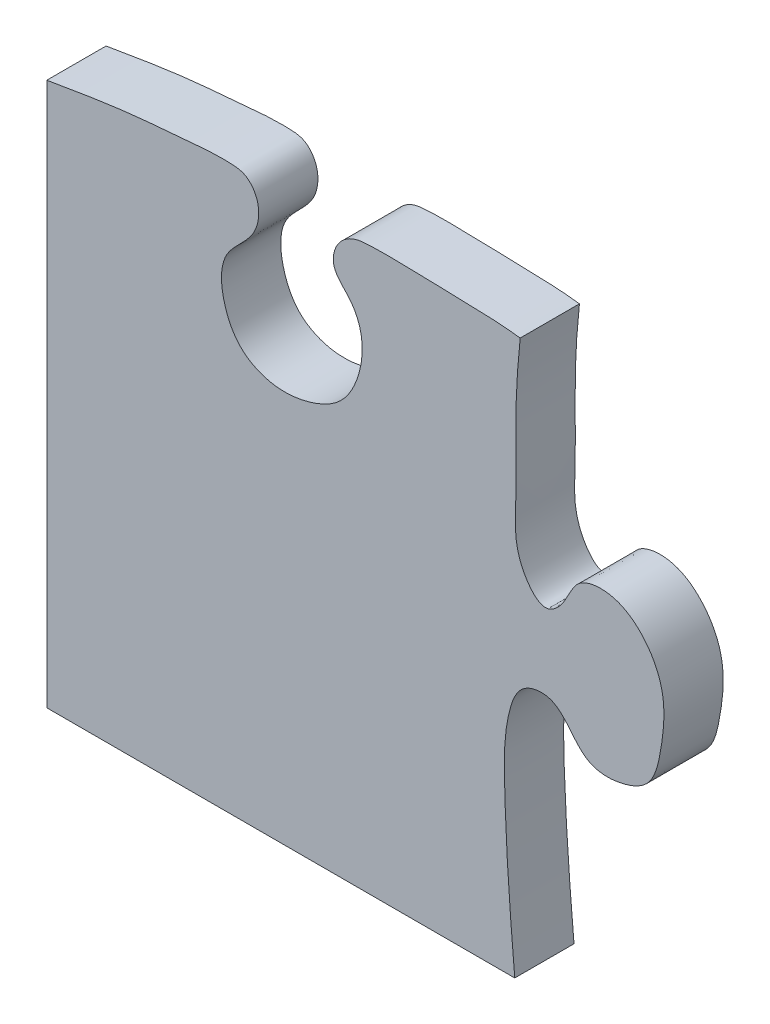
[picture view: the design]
ISO-10303-21;
HEADER;
FILE_DESCRIPTION(('STEP AP214'),'2;1');
FILE_NAME('part.step','',(''),(''),'','','');
FILE_SCHEMA(('AUTOMOTIVE_DESIGN { 1 0 10303 214 1 1 1 1 }'));
ENDSEC;
DATA;
#1=APPLICATION_CONTEXT('core data for automotive mechanical design processes');
#2=APPLICATION_PROTOCOL_DEFINITION('international standard','automotive_design',2000,#1);
#3=PRODUCT_CONTEXT('',#1,'mechanical');
#4=PRODUCT('Part','Part','',(#3));
#5=PRODUCT_RELATED_PRODUCT_CATEGORY('part','',(#4));
#6=PRODUCT_DEFINITION_FORMATION('','',#4);
#7=PRODUCT_DEFINITION_CONTEXT('part definition',#1,'design');
#8=PRODUCT_DEFINITION('design','',#6,#7);
#9=PRODUCT_DEFINITION_SHAPE('','',#8);
#10=(LENGTH_UNIT() NAMED_UNIT(*) SI_UNIT(.MILLI.,.METRE.));
#11=(NAMED_UNIT(*) PLANE_ANGLE_UNIT() SI_UNIT($,.RADIAN.));
#12=(NAMED_UNIT(*) SI_UNIT($,.STERADIAN.) SOLID_ANGLE_UNIT());
#13=UNCERTAINTY_MEASURE_WITH_UNIT(LENGTH_MEASURE(1.E-05),#10,'distance_accuracy_value','');
#14=(GEOMETRIC_REPRESENTATION_CONTEXT(3) GLOBAL_UNCERTAINTY_ASSIGNED_CONTEXT((#13)) GLOBAL_UNIT_ASSIGNED_CONTEXT((#10,
#11,#12)) REPRESENTATION_CONTEXT('',''));
#15=CARTESIAN_POINT('',(0.,0.,0.));
#16=DIRECTION('',(0.,0.,1.));
#17=DIRECTION('',(1.,0.,0.));
#18=AXIS2_PLACEMENT_3D('',#15,#16,#17);
#19=CARTESIAN_POINT('',(-352.534626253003,356.,-0.00999999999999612));
#20=CARTESIAN_POINT('',(-353.877781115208,341.802611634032,-0.00999999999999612));
#21=CARTESIAN_POINT('',(-351.460483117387,322.567956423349,-0.00999999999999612));
#22=CARTESIAN_POINT('',(-355.747404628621,299.493999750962,-0.00999999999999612));
#23=CARTESIAN_POINT('',(-347.645743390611,289.357079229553,-0.00999999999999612));
#24=CARTESIAN_POINT('',(-337.80105524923,293.322704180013,-0.00999999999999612));
#25=CARTESIAN_POINT('',(-331.763521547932,304.464683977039,-0.00999999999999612));
#26=CARTESIAN_POINT('',(-312.737993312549,300.417040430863,-0.00999999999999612));
#27=CARTESIAN_POINT('',(-304.311514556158,284.867329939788,-0.00999999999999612));
#28=CARTESIAN_POINT('',(-301.362858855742,267.518539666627,-0.00999999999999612));
#29=CARTESIAN_POINT('',(-309.525260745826,253.299800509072,-0.00999999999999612));
#30=CARTESIAN_POINT('',(-323.085028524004,249.130779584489,-0.00999999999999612));
#31=CARTESIAN_POINT('',(-333.558735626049,254.453066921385,-0.00999999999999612));
#32=CARTESIAN_POINT('',(-338.061007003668,263.306234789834,-0.00999999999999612));
#33=CARTESIAN_POINT('',(-357.610347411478,266.663664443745,-0.00999999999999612));
#34=CARTESIAN_POINT('',(-352.91397083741,227.568949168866,-0.00999999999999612));
#35=CARTESIAN_POINT('',(-349.689076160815,203.209436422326,-0.00999999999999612));
#36=CARTESIAN_POINT('',(-346.386977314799,175.800103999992,-0.00999999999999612));
#37=CARTESIAN_POINT('',(-343.691373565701,150.269708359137,-0.00999999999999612));
#38=CARTESIAN_POINT('',(-342.931567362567,128.594211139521,-0.00999999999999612));
#39=CARTESIAN_POINT('',(-343.655360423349,107.633085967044,-0.00999999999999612));
#40=CARTESIAN_POINT('',(-357.389603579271,103.824438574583,-0.00999999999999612));
#41=CARTESIAN_POINT('',(-367.576419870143,106.015828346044,-0.00999999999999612));
#42=CARTESIAN_POINT('',(-371.765750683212,114.589953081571,-0.00999999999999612));
#43=CARTESIAN_POINT('',(-382.535012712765,116.182843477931,-0.00999999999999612));
#44=CARTESIAN_POINT('',(-394.783984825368,115.916744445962,-0.00999999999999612));
#45=CARTESIAN_POINT('',(-402.322369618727,104.396558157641,-0.00999999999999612));
#46=CARTESIAN_POINT('',(-405.688784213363,89.1486295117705,-0.00999999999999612));
#47=CARTESIAN_POINT('',(-402.964002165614,71.2455616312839,-0.00999999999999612));
#48=CARTESIAN_POINT('',(-389.022909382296,60.8761001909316,-0.00999999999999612));
#49=CARTESIAN_POINT('',(-377.013010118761,63.0649709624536,-0.00999999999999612));
#50=CARTESIAN_POINT('',(-370.136212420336,70.9200889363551,-0.00999999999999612));
#51=CARTESIAN_POINT('',(-359.248489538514,74.3793713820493,-0.00999999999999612));
#52=CARTESIAN_POINT('',(-347.964757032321,70.4189230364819,-0.00999999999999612));
#53=CARTESIAN_POINT('',(-342.961480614,58.8762689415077,-0.00999999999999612));
#54=CARTESIAN_POINT('',(-344.957853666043,42.6141567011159,-0.00999999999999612));
#55=CARTESIAN_POINT('',(-348.090347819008,20.9428011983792,-0.00999999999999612));
#56=CARTESIAN_POINT('',(-348.787112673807,-1.92187291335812,-0.00999999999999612));
#57=CARTESIAN_POINT('',(-347.063507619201,-23.1354473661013,-0.00999999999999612));
#58=CARTESIAN_POINT('',(-345.803834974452,-40.1989543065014,-0.00999999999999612));
#59=CARTESIAN_POINT('',(-346.365109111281,-52.5147126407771,-0.00999999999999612));
#60=CARTESIAN_POINT('',(-346.987719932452,-61.0081322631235,-0.00999999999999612));
#61=CARTESIAN_POINT('',(-354.605588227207,-67.8105997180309,-0.00999999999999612));
#62=CARTESIAN_POINT('',(-368.483652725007,-69.9483525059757,-0.00999999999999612));
#63=CARTESIAN_POINT('',(-374.929468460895,-56.6181815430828,-0.00999999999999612));
#64=CARTESIAN_POINT('',(-389.51528778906,-54.9578642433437,-0.00999999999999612));
#65=CARTESIAN_POINT('',(-403.927113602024,-62.7741481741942,-0.00999999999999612));
#66=CARTESIAN_POINT('',(-408.906740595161,-79.6272624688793,-0.00999999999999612));
#67=CARTESIAN_POINT('',(-407.354009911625,-95.181625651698,-0.00999999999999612));
#68=CARTESIAN_POINT('',(-399.108136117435,-108.127376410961,-0.00999999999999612));
#69=CARTESIAN_POINT('',(-382.721304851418,-112.332091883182,-0.00999999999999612));
#70=CARTESIAN_POINT('',(-372.627066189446,-99.6029758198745,-0.00999999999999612));
#71=CARTESIAN_POINT('',(-359.245942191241,-98.6507630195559,-0.00999999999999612));
#72=CARTESIAN_POINT('',(-346.811479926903,-105.357996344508,-0.00999999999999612));
#73=CARTESIAN_POINT('',(-347.06309899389,-122.824759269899,-0.00999999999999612));
#74=CARTESIAN_POINT('',(-349.512128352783,-142.867981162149,-0.00999999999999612));
#75=CARTESIAN_POINT('',(-351.967561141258,-164.813498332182,-0.00999999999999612));
#76=CARTESIAN_POINT('',(-354.173348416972,-189.531702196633,-0.00999999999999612));
#77=CARTESIAN_POINT('',(-353.048503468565,-212.668893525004,-0.00999999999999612));
#78=CARTESIAN_POINT('',(-354.739062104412,-232.840407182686,-0.00999999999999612));
#79=CARTESIAN_POINT('',(-344.245211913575,-244.921596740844,-0.00999999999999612));
#80=CARTESIAN_POINT('',(-336.376475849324,-237.735778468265,-0.00999999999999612));
#81=CARTESIAN_POINT('',(-333.938993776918,-228.321764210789,-0.00999999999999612));
#82=CARTESIAN_POINT('',(-321.423877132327,-226.689197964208,-0.00999999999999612));
#83=CARTESIAN_POINT('',(-310.83224361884,-232.911014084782,-0.00999999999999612));
#84=CARTESIAN_POINT('',(-302.540379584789,-246.611975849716,-0.00999999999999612));
#85=CARTESIAN_POINT('',(-304.049270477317,-262.348985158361,-0.00999999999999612));
#86=CARTESIAN_POINT('',(-307.19247660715,-276.895908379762,-0.00999999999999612));
#87=CARTESIAN_POINT('',(-317.916754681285,-281.774853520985,-0.00999999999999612));
#88=CARTESIAN_POINT('',(-328.48323529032,-282.130896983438,-0.00999999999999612));
#89=CARTESIAN_POINT('',(-335.177873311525,-274.391757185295,-0.00999999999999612));
#90=CARTESIAN_POINT('',(-340.967044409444,-267.020526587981,-0.00999999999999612));
#91=CARTESIAN_POINT('',(-352.493784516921,-268.657509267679,-0.00999999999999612));
#92=CARTESIAN_POINT('',(-357.686319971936,-282.822093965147,-0.00999999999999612));
#93=CARTESIAN_POINT('',(-357.597756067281,-311.53856504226,-0.00999999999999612));
#94=CARTESIAN_POINT('',(-355.656952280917,-337.76537977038,-0.00999999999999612));
#95=CARTESIAN_POINT('',(-354.035135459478,-356.,-0.00999999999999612));
#96=B_SPLINE_CURVE_WITH_KNOTS('',3,(#19,#20,#21,#22,#23,#24,#25,#26,#27,#28,#29,#30,#31,#32,#33,
#34,#35,#36,#37,#38,#39,#40,#41,#42,#43,#44,#45,#46,#47,#48,#49,#50,#51,#52,#53,#54,#55,#56,#57,
#58,#59,#60,#61,#62,#63,#64,#65,#66,#67,#68,#69,#70,#71,#72,#73,#74,#75,#76,#77,#78,#79,#80,#81,
#82,#83,#84,#85,#86,#87,#88,#89,#90,#91,#92,#93,#94,#95),.UNSPECIFIED.,.F.,.F.,(4,1,1,1,1,1,1,1,
1,1,1,1,1,1,1,1,1,1,1,1,1,1,1,1,1,1,1,1,1,1,1,1,1,1,1,1,1,1,1,1,1,1,1,1,1,1,1,1,1,1,1,1,1,1,1,1,
1,1,1,1,1,1,1,1,1,1,1,1,1,1,1,1,1,1,4),(0.,0.0362663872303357,0.0516957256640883,
0.0575126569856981,0.0656061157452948,0.0738542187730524,0.0886191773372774,0.103761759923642,
0.118344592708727,0.132658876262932,0.141706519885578,0.152628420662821,0.159936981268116,
0.166346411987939,0.196099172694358,0.222591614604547,0.242329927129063,0.265519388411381,
0.28892287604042,0.3014399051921,0.313339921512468,0.3200215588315,0.327007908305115,
0.335496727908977,0.346341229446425,0.356695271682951,0.367736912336,0.387395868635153,
0.399447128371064,0.408443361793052,0.416078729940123,0.425886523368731,0.4364139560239,
0.44355209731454,0.456701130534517,0.478081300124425,0.500737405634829,0.515722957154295,
0.53328305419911,0.545176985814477,0.547408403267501,0.555597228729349,0.568417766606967,
0.576959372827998,0.589646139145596,0.601337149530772,0.617107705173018,0.631663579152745,
0.64088779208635,0.655943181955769,0.666193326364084,0.679689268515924,0.687162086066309,
0.700019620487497,0.719317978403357,0.742088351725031,0.756487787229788,0.783860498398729,
0.801622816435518,0.8097052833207,0.815461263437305,0.824516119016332,0.833497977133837,
0.842909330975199,0.85562007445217,0.872330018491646,0.883598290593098,0.890881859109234,
0.901363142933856,0.908021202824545,0.916645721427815,0.924017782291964,0.933106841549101,
0.95201687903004,1.),.UNSPECIFIED.);
#97=DIRECTION('',(0.,0.,1.));
#98=VECTOR('',#97,1.);
#99=SURFACE_OF_LINEAR_EXTRUSION('',#96,#98);
#100=CARTESIAN_POINT('',(-352.534626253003,356.,20.));
#101=CARTESIAN_POINT('',(-353.877781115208,341.802611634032,20.));
#102=CARTESIAN_POINT('',(-351.460483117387,322.567956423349,20.));
#103=CARTESIAN_POINT('',(-355.747404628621,299.493999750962,20.));
#104=CARTESIAN_POINT('',(-347.645743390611,289.357079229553,20.));
#105=CARTESIAN_POINT('',(-337.80105524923,293.322704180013,20.));
#106=CARTESIAN_POINT('',(-331.763521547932,304.464683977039,20.));
#107=CARTESIAN_POINT('',(-312.737993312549,300.417040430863,20.));
#108=CARTESIAN_POINT('',(-304.311514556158,284.867329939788,20.));
#109=CARTESIAN_POINT('',(-301.362858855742,267.518539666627,20.));
#110=CARTESIAN_POINT('',(-309.525260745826,253.299800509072,20.));
#111=CARTESIAN_POINT('',(-323.085028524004,249.130779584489,20.));
#112=CARTESIAN_POINT('',(-333.558735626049,254.453066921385,20.));
#113=CARTESIAN_POINT('',(-338.061007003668,263.306234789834,20.));
#114=CARTESIAN_POINT('',(-357.610347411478,266.663664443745,20.));
#115=CARTESIAN_POINT('',(-352.91397083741,227.568949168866,20.));
#116=CARTESIAN_POINT('',(-349.689076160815,203.209436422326,20.));
#117=CARTESIAN_POINT('',(-346.386977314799,175.800103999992,20.));
#118=CARTESIAN_POINT('',(-343.691373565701,150.269708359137,20.));
#119=CARTESIAN_POINT('',(-342.931567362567,128.594211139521,20.));
#120=CARTESIAN_POINT('',(-343.655360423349,107.633085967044,20.));
#121=CARTESIAN_POINT('',(-357.389603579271,103.824438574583,20.));
#122=CARTESIAN_POINT('',(-367.576419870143,106.015828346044,20.));
#123=CARTESIAN_POINT('',(-371.765750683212,114.589953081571,20.));
#124=CARTESIAN_POINT('',(-382.535012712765,116.182843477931,20.));
#125=CARTESIAN_POINT('',(-394.783984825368,115.916744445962,20.));
#126=CARTESIAN_POINT('',(-402.322369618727,104.396558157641,20.));
#127=CARTESIAN_POINT('',(-405.688784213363,89.1486295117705,20.));
#128=CARTESIAN_POINT('',(-402.964002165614,71.2455616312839,20.));
#129=CARTESIAN_POINT('',(-389.022909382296,60.8761001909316,20.));
#130=CARTESIAN_POINT('',(-377.013010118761,63.0649709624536,20.));
#131=CARTESIAN_POINT('',(-370.136212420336,70.9200889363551,20.));
#132=CARTESIAN_POINT('',(-359.248489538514,74.3793713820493,20.));
#133=CARTESIAN_POINT('',(-347.964757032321,70.4189230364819,20.));
#134=CARTESIAN_POINT('',(-342.961480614,58.8762689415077,20.));
#135=CARTESIAN_POINT('',(-344.957853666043,42.6141567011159,20.));
#136=CARTESIAN_POINT('',(-348.090347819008,20.9428011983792,20.));
#137=CARTESIAN_POINT('',(-348.787112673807,-1.92187291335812,20.));
#138=CARTESIAN_POINT('',(-347.063507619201,-23.1354473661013,20.));
#139=CARTESIAN_POINT('',(-345.803834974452,-40.1989543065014,20.));
#140=CARTESIAN_POINT('',(-346.365109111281,-52.5147126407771,20.));
#141=CARTESIAN_POINT('',(-346.987719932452,-61.0081322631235,20.));
#142=CARTESIAN_POINT('',(-354.605588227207,-67.8105997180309,20.));
#143=CARTESIAN_POINT('',(-368.483652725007,-69.9483525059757,20.));
#144=CARTESIAN_POINT('',(-374.929468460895,-56.6181815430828,20.));
#145=CARTESIAN_POINT('',(-389.51528778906,-54.9578642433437,20.));
#146=CARTESIAN_POINT('',(-403.927113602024,-62.7741481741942,20.));
#147=CARTESIAN_POINT('',(-408.906740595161,-79.6272624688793,20.));
#148=CARTESIAN_POINT('',(-407.354009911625,-95.181625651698,20.));
#149=CARTESIAN_POINT('',(-399.108136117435,-108.127376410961,20.));
#150=CARTESIAN_POINT('',(-382.721304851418,-112.332091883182,20.));
#151=CARTESIAN_POINT('',(-372.627066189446,-99.6029758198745,20.));
#152=CARTESIAN_POINT('',(-359.245942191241,-98.6507630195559,20.));
#153=CARTESIAN_POINT('',(-346.811479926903,-105.357996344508,20.));
#154=CARTESIAN_POINT('',(-347.06309899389,-122.824759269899,20.));
#155=CARTESIAN_POINT('',(-349.512128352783,-142.867981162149,20.));
#156=CARTESIAN_POINT('',(-351.967561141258,-164.813498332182,20.));
#157=CARTESIAN_POINT('',(-354.173348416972,-189.531702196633,20.));
#158=CARTESIAN_POINT('',(-353.048503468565,-212.668893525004,20.));
#159=CARTESIAN_POINT('',(-354.739062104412,-232.840407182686,20.));
#160=CARTESIAN_POINT('',(-344.245211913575,-244.921596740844,20.));
#161=CARTESIAN_POINT('',(-336.376475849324,-237.735778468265,20.));
#162=CARTESIAN_POINT('',(-333.938993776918,-228.321764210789,20.));
#163=CARTESIAN_POINT('',(-321.423877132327,-226.689197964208,20.));
#164=CARTESIAN_POINT('',(-310.83224361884,-232.911014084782,20.));
#165=CARTESIAN_POINT('',(-302.540379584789,-246.611975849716,20.));
#166=CARTESIAN_POINT('',(-304.049270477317,-262.348985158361,20.));
#167=CARTESIAN_POINT('',(-307.19247660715,-276.895908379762,20.));
#168=CARTESIAN_POINT('',(-317.916754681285,-281.774853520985,20.));
#169=CARTESIAN_POINT('',(-328.48323529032,-282.130896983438,20.));
#170=CARTESIAN_POINT('',(-335.177873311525,-274.391757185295,20.));
#171=CARTESIAN_POINT('',(-340.967044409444,-267.020526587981,20.));
#172=CARTESIAN_POINT('',(-352.493784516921,-268.657509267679,20.));
#173=CARTESIAN_POINT('',(-357.686319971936,-282.822093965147,20.));
#174=CARTESIAN_POINT('',(-357.597756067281,-311.53856504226,20.));
#175=CARTESIAN_POINT('',(-355.656952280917,-337.76537977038,20.));
#176=CARTESIAN_POINT('',(-354.035135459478,-356.,20.));
#177=B_SPLINE_CURVE_WITH_KNOTS('',3,(#100,#101,#102,#103,#104,#105,#106,#107,#108,#109,#110,
#111,#112,#113,#114,#115,#116,#117,#118,#119,#120,#121,#122,#123,#124,#125,#126,#127,#128,#129,
#130,#131,#132,#133,#134,#135,#136,#137,#138,#139,#140,#141,#142,#143,#144,#145,#146,#147,#148,
#149,#150,#151,#152,#153,#154,#155,#156,#157,#158,#159,#160,#161,#162,#163,#164,#165,#166,#167,
#168,#169,#170,#171,#172,#173,#174,#175,#176),.UNSPECIFIED.,.F.,.F.,(4,1,1,1,1,1,1,1,1,1,1,1,1,
1,1,1,1,1,1,1,1,1,1,1,1,1,1,1,1,1,1,1,1,1,1,1,1,1,1,1,1,1,1,1,1,1,1,1,1,1,1,1,1,1,1,1,1,1,1,1,1,
1,1,1,1,1,1,1,1,1,1,1,1,1,4),(0.,0.0362663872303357,0.0516957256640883,0.0575126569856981,
0.0656061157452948,0.0738542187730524,0.0886191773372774,0.103761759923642,0.118344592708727,
0.132658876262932,0.141706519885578,0.152628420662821,0.159936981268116,0.166346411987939,
0.196099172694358,0.222591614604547,0.242329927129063,0.265519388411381,0.28892287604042,
0.3014399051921,0.313339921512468,0.3200215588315,0.327007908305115,0.335496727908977,
0.346341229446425,0.356695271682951,0.367736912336,0.387395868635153,0.399447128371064,
0.408443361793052,0.416078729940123,0.425886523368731,0.4364139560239,0.44355209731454,
0.456701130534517,0.478081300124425,0.500737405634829,0.515722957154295,0.53328305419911,
0.545176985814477,0.547408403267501,0.555597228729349,0.568417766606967,0.576959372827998,
0.589646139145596,0.601337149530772,0.617107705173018,0.631663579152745,0.64088779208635,
0.655943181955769,0.666193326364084,0.679689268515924,0.687162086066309,0.700019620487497,
0.719317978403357,0.742088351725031,0.756487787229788,0.783860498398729,0.801622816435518,
0.8097052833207,0.815461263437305,0.824516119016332,0.833497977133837,0.842909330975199,
0.85562007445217,0.872330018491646,0.883598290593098,0.890881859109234,0.901363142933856,
0.908021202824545,0.916645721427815,0.924017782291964,0.933106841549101,0.95201687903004,1.),.UNSPECIFIED.);
#178=CARTESIAN_POINT('',(-352.201722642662,-167.987791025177,20.));
#179=VERTEX_POINT('',#178);
#180=CARTESIAN_POINT('',(-354.035135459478,-356.,20.));
#181=VERTEX_POINT('',#180);
#182=EDGE_CURVE('E80',#179,#181,#177,.T.);
#183=ORIENTED_EDGE('',*,*,#182,.T.);
#184=DIRECTION('',(0.,0.,1.));
#185=VECTOR('',#184,1.);
#186=CARTESIAN_POINT('',(-354.035135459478,-356.,-0.00999999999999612));
#187=LINE('',#186,#185);
#188=CARTESIAN_POINT('',(-354.035135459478,-356.,0.));
#189=VERTEX_POINT('',#188);
#190=EDGE_CURVE('E83',#189,#181,#187,.T.);
#191=ORIENTED_EDGE('',*,*,#190,.F.);
#192=CARTESIAN_POINT('',(-352.534626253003,356.,0.));
#193=CARTESIAN_POINT('',(-353.877781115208,341.802611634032,0.));
#194=CARTESIAN_POINT('',(-351.460483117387,322.567956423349,0.));
#195=CARTESIAN_POINT('',(-355.747404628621,299.493999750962,0.));
#196=CARTESIAN_POINT('',(-347.645743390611,289.357079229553,0.));
#197=CARTESIAN_POINT('',(-337.80105524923,293.322704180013,0.));
#198=CARTESIAN_POINT('',(-331.763521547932,304.464683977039,0.));
#199=CARTESIAN_POINT('',(-312.737993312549,300.417040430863,0.));
#200=CARTESIAN_POINT('',(-304.311514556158,284.867329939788,0.));
#201=CARTESIAN_POINT('',(-301.362858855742,267.518539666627,0.));
#202=CARTESIAN_POINT('',(-309.525260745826,253.299800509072,0.));
#203=CARTESIAN_POINT('',(-323.085028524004,249.130779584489,0.));
#204=CARTESIAN_POINT('',(-333.558735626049,254.453066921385,0.));
#205=CARTESIAN_POINT('',(-338.061007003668,263.306234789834,0.));
#206=CARTESIAN_POINT('',(-357.610347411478,266.663664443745,0.));
#207=CARTESIAN_POINT('',(-352.91397083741,227.568949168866,0.));
#208=CARTESIAN_POINT('',(-349.689076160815,203.209436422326,0.));
#209=CARTESIAN_POINT('',(-346.386977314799,175.800103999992,0.));
#210=CARTESIAN_POINT('',(-343.691373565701,150.269708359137,0.));
#211=CARTESIAN_POINT('',(-342.931567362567,128.594211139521,0.));
#212=CARTESIAN_POINT('',(-343.655360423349,107.633085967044,0.));
#213=CARTESIAN_POINT('',(-357.389603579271,103.824438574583,0.));
#214=CARTESIAN_POINT('',(-367.576419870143,106.015828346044,0.));
#215=CARTESIAN_POINT('',(-371.765750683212,114.589953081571,0.));
#216=CARTESIAN_POINT('',(-382.535012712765,116.182843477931,0.));
#217=CARTESIAN_POINT('',(-394.783984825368,115.916744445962,0.));
#218=CARTESIAN_POINT('',(-402.322369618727,104.396558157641,0.));
#219=CARTESIAN_POINT('',(-405.688784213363,89.1486295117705,0.));
#220=CARTESIAN_POINT('',(-402.964002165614,71.2455616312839,0.));
#221=CARTESIAN_POINT('',(-389.022909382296,60.8761001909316,0.));
#222=CARTESIAN_POINT('',(-377.013010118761,63.0649709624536,0.));
#223=CARTESIAN_POINT('',(-370.136212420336,70.9200889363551,0.));
#224=CARTESIAN_POINT('',(-359.248489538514,74.3793713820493,0.));
#225=CARTESIAN_POINT('',(-347.964757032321,70.4189230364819,0.));
#226=CARTESIAN_POINT('',(-342.961480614,58.8762689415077,0.));
#227=CARTESIAN_POINT('',(-344.957853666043,42.6141567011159,0.));
#228=CARTESIAN_POINT('',(-348.090347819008,20.9428011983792,0.));
#229=CARTESIAN_POINT('',(-348.787112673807,-1.92187291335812,0.));
#230=CARTESIAN_POINT('',(-347.063507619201,-23.1354473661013,0.));
#231=CARTESIAN_POINT('',(-345.803834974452,-40.1989543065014,0.));
#232=CARTESIAN_POINT('',(-346.365109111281,-52.5147126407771,0.));
#233=CARTESIAN_POINT('',(-346.987719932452,-61.0081322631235,0.));
#234=CARTESIAN_POINT('',(-354.605588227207,-67.8105997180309,0.));
#235=CARTESIAN_POINT('',(-368.483652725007,-69.9483525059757,0.));
#236=CARTESIAN_POINT('',(-374.929468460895,-56.6181815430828,0.));
#237=CARTESIAN_POINT('',(-389.51528778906,-54.9578642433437,0.));
#238=CARTESIAN_POINT('',(-403.927113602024,-62.7741481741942,0.));
#239=CARTESIAN_POINT('',(-408.906740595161,-79.6272624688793,0.));
#240=CARTESIAN_POINT('',(-407.354009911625,-95.181625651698,0.));
#241=CARTESIAN_POINT('',(-399.108136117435,-108.127376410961,0.));
#242=CARTESIAN_POINT('',(-382.721304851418,-112.332091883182,0.));
#243=CARTESIAN_POINT('',(-372.627066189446,-99.6029758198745,0.));
#244=CARTESIAN_POINT('',(-359.245942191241,-98.6507630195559,0.));
#245=CARTESIAN_POINT('',(-346.811479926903,-105.357996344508,0.));
#246=CARTESIAN_POINT('',(-347.06309899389,-122.824759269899,0.));
#247=CARTESIAN_POINT('',(-349.512128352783,-142.867981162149,0.));
#248=CARTESIAN_POINT('',(-351.967561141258,-164.813498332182,0.));
#249=CARTESIAN_POINT('',(-354.173348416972,-189.531702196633,0.));
#250=CARTESIAN_POINT('',(-353.048503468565,-212.668893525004,0.));
#251=CARTESIAN_POINT('',(-354.739062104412,-232.840407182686,0.));
#252=CARTESIAN_POINT('',(-344.245211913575,-244.921596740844,0.));
#253=CARTESIAN_POINT('',(-336.376475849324,-237.735778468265,0.));
#254=CARTESIAN_POINT('',(-333.938993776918,-228.321764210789,0.));
#255=CARTESIAN_POINT('',(-321.423877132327,-226.689197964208,0.));
#256=CARTESIAN_POINT('',(-310.83224361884,-232.911014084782,0.));
#257=CARTESIAN_POINT('',(-302.540379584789,-246.611975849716,0.));
#258=CARTESIAN_POINT('',(-304.049270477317,-262.348985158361,0.));
#259=CARTESIAN_POINT('',(-307.19247660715,-276.895908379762,0.));
#260=CARTESIAN_POINT('',(-317.916754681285,-281.774853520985,0.));
#261=CARTESIAN_POINT('',(-328.48323529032,-282.130896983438,0.));
#262=CARTESIAN_POINT('',(-335.177873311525,-274.391757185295,0.));
#263=CARTESIAN_POINT('',(-340.967044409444,-267.020526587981,0.));
#264=CARTESIAN_POINT('',(-352.493784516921,-268.657509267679,0.));
#265=CARTESIAN_POINT('',(-357.686319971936,-282.822093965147,0.));
#266=CARTESIAN_POINT('',(-357.597756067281,-311.53856504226,0.));
#267=CARTESIAN_POINT('',(-355.656952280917,-337.76537977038,0.));
#268=CARTESIAN_POINT('',(-354.035135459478,-356.,0.));
#269=B_SPLINE_CURVE_WITH_KNOTS('',3,(#192,#193,#194,#195,#196,#197,#198,#199,#200,#201,#202,
#203,#204,#205,#206,#207,#208,#209,#210,#211,#212,#213,#214,#215,#216,#217,#218,#219,#220,#221,
#222,#223,#224,#225,#226,#227,#228,#229,#230,#231,#232,#233,#234,#235,#236,#237,#238,#239,#240,
#241,#242,#243,#244,#245,#246,#247,#248,#249,#250,#251,#252,#253,#254,#255,#256,#257,#258,#259,
#260,#261,#262,#263,#264,#265,#266,#267,#268),.UNSPECIFIED.,.F.,.F.,(4,1,1,1,1,1,1,1,1,1,1,1,1,
1,1,1,1,1,1,1,1,1,1,1,1,1,1,1,1,1,1,1,1,1,1,1,1,1,1,1,1,1,1,1,1,1,1,1,1,1,1,1,1,1,1,1,1,1,1,1,1,
1,1,1,1,1,1,1,1,1,1,1,1,1,4),(0.,0.0362663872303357,0.0516957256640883,0.0575126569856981,
0.0656061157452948,0.0738542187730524,0.0886191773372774,0.103761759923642,0.118344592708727,
0.132658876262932,0.141706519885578,0.152628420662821,0.159936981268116,0.166346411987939,
0.196099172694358,0.222591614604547,0.242329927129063,0.265519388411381,0.28892287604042,
0.3014399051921,0.313339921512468,0.3200215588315,0.327007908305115,0.335496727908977,
0.346341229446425,0.356695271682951,0.367736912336,0.387395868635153,0.399447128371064,
0.408443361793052,0.416078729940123,0.425886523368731,0.4364139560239,0.44355209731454,
0.456701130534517,0.478081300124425,0.500737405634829,0.515722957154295,0.53328305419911,
0.545176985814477,0.547408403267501,0.555597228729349,0.568417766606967,0.576959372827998,
0.589646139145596,0.601337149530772,0.617107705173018,0.631663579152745,0.64088779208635,
0.655943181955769,0.666193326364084,0.679689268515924,0.687162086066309,0.700019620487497,
0.719317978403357,0.742088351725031,0.756487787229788,0.783860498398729,0.801622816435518,
0.8097052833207,0.815461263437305,0.824516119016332,0.833497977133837,0.842909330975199,
0.85562007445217,0.872330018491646,0.883598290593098,0.890881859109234,0.901363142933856,
0.908021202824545,0.916645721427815,0.924017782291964,0.933106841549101,0.95201687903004,1.),.UNSPECIFIED.);
#270=CARTESIAN_POINT('',(-352.201722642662,-167.987791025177,0.));
#271=VERTEX_POINT('',#270);
#272=EDGE_CURVE('E82',#271,#189,#269,.T.);
#273=ORIENTED_EDGE('',*,*,#272,.F.);
#274=DIRECTION('',(0.,0.,1.));
#275=VECTOR('',#274,1.);
#276=CARTESIAN_POINT('',(-352.201722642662,-167.987791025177,-0.00999999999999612));
#277=LINE('',#276,#275);
#278=EDGE_CURVE('E78',#179,#271,#277,.F.);
#279=ORIENTED_EDGE('',*,*,#278,.F.);
#280=EDGE_LOOP('',(#183,#191,#273,#279));
#281=FACE_BOUND('',#280,.T.);
#282=ADVANCED_FACE('F34',(#281),#99,.F.);
#283=CARTESIAN_POINT('',(-512.,-172.519287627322,-0.00999999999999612));
#284=CARTESIAN_POINT('',(-502.879283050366,-170.962470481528,-0.00999999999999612));
#285=CARTESIAN_POINT('',(-487.788222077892,-168.37828827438,-0.00999999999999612));
#286=CARTESIAN_POINT('',(-467.037528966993,-166.739801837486,-0.00999999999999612));
#287=CARTESIAN_POINT('',(-454.159365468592,-165.446436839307,-0.00999999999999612));
#288=CARTESIAN_POINT('',(-444.971534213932,-166.107812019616,-0.00999999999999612));
#289=CARTESIAN_POINT('',(-439.850321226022,-171.772015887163,-0.00999999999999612));
#290=CARTESIAN_POINT('',(-440.374957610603,-181.037323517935,-0.00999999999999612));
#291=CARTESIAN_POINT('',(-446.328241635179,-187.391856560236,-0.00999999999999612));
#292=CARTESIAN_POINT('',(-453.905227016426,-194.752671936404,-0.00999999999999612));
#293=CARTESIAN_POINT('',(-453.078389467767,-207.700641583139,-0.00999999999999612));
#294=CARTESIAN_POINT('',(-447.147625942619,-218.930001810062,-0.00999999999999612));
#295=CARTESIAN_POINT('',(-435.337181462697,-224.50074852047,-0.00999999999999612));
#296=CARTESIAN_POINT('',(-423.146614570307,-223.01936726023,-0.00999999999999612));
#297=CARTESIAN_POINT('',(-411.980938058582,-217.277205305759,-0.00999999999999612));
#298=CARTESIAN_POINT('',(-406.065466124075,-206.648631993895,-0.00999999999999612));
#299=CARTESIAN_POINT('',(-404.677696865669,-194.893000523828,-0.00999999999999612));
#300=CARTESIAN_POINT('',(-408.988751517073,-185.080089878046,-0.00999999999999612));
#301=CARTESIAN_POINT('',(-416.250714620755,-179.677092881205,-0.00999999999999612));
#302=CARTESIAN_POINT('',(-414.534960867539,-170.559036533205,-0.00999999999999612));
#303=CARTESIAN_POINT('',(-409.029101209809,-166.771377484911,-0.00999999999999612));
#304=CARTESIAN_POINT('',(-399.765557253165,-166.088529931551,-0.00999999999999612));
#305=CARTESIAN_POINT('',(-387.895154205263,-166.365956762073,-0.00999999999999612));
#306=CARTESIAN_POINT('',(-370.467023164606,-166.815486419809,-0.00999999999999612));
#307=CARTESIAN_POINT('',(-353.468929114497,-167.36046909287,-0.00999999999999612));
#308=CARTESIAN_POINT('',(-335.945481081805,-171.004639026,-0.00999999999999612));
#309=CARTESIAN_POINT('',(-314.642568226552,-174.308910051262,-0.00999999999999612));
#310=CARTESIAN_POINT('',(-295.191530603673,-175.373190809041,-0.00999999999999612));
#311=CARTESIAN_POINT('',(-279.655129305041,-174.532366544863,-0.00999999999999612));
#312=CARTESIAN_POINT('',(-272.871357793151,-169.661223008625,-0.00999999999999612));
#313=CARTESIAN_POINT('',(-269.507556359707,-161.549368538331,-0.00999999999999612));
#314=CARTESIAN_POINT('',(-275.843021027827,-154.65628056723,-0.00999999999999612));
#315=CARTESIAN_POINT('',(-280.95754914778,-144.902856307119,-0.00999999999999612));
#316=CARTESIAN_POINT('',(-276.534312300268,-130.977346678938,-0.00999999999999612));
#317=CARTESIAN_POINT('',(-261.937250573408,-125.579540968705,-0.00999999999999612));
#318=CARTESIAN_POINT('',(-247.663642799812,-124.917748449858,-0.00999999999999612));
#319=CARTESIAN_POINT('',(-234.462562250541,-132.547465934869,-0.00999999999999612));
#320=CARTESIAN_POINT('',(-231.429981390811,-144.191054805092,-0.00999999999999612));
#321=CARTESIAN_POINT('',(-232.066307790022,-154.613730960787,-0.00999999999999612));
#322=CARTESIAN_POINT('',(-238.05545254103,-160.208195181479,-0.00999999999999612));
#323=CARTESIAN_POINT('',(-239.725495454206,-167.504540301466,-0.00999999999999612));
#324=CARTESIAN_POINT('',(-236.616853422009,-176.333406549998,-0.00999999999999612));
#325=CARTESIAN_POINT('',(-223.934770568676,-178.282283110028,-0.00999999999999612));
#326=CARTESIAN_POINT('',(-211.556635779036,-176.87255281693,-0.00999999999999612));
#327=CARTESIAN_POINT('',(-197.283196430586,-172.884179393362,-0.00999999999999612));
#328=CARTESIAN_POINT('',(-182.605892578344,-171.15728588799,-0.00999999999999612));
#329=CARTESIAN_POINT('',(-164.840984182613,-173.659101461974,-0.00999999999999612));
#330=CARTESIAN_POINT('',(-147.945056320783,-175.383809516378,-0.00999999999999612));
#331=CARTESIAN_POINT('',(-131.023155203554,-175.064925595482,-0.00999999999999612));
#332=CARTESIAN_POINT('',(-118.854077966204,-171.888086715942,-0.00999999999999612));
#333=CARTESIAN_POINT('',(-110.251650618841,-164.015375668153,-0.00999999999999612));
#334=CARTESIAN_POINT('',(-112.366058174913,-152.74022327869,-0.00999999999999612));
#335=CARTESIAN_POINT('',(-124.029184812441,-149.21363367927,-0.00999999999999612));
#336=CARTESIAN_POINT('',(-130.728576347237,-135.686086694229,-0.00999999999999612));
#337=CARTESIAN_POINT('',(-127.173489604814,-119.738819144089,-0.00999999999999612));
#338=CARTESIAN_POINT('',(-112.643680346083,-109.612236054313,-0.00999999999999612));
#339=CARTESIAN_POINT('',(-97.8925044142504,-110.264465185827,-0.00999999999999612));
#340=CARTESIAN_POINT('',(-85.3244606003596,-114.886626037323,-0.00999999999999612));
#341=CARTESIAN_POINT('',(-77.7012738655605,-123.996273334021,-0.00999999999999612));
#342=CARTESIAN_POINT('',(-75.1871896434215,-136.082021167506,-0.00999999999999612));
#343=CARTESIAN_POINT('',(-83.4449300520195,-145.685757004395,-0.00999999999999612));
#344=CARTESIAN_POINT('',(-93.6696383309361,-152.57821138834,-0.00999999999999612));
#345=CARTESIAN_POINT('',(-93.6908124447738,-166.777041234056,-0.00999999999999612));
#346=CARTESIAN_POINT('',(-84.1667136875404,-170.982620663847,-0.00999999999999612));
#347=CARTESIAN_POINT('',(-77.6752461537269,-173.278649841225,-0.00999999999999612));
#348=CARTESIAN_POINT('',(-68.1506335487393,-173.35598232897,-0.00999999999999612));
#349=CARTESIAN_POINT('',(-50.9086392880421,-172.467654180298,-0.00999999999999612));
#350=CARTESIAN_POINT('',(-29.3703336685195,-168.255680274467,-0.00999999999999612));
#351=CARTESIAN_POINT('',(-5.85808978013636,-161.016855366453,-0.00999999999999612));
#352=CARTESIAN_POINT('',(10.8279950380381,-157.928962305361,-0.00999999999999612));
#353=CARTESIAN_POINT('',(25.2118575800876,-156.177147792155,-0.00999999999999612));
#354=CARTESIAN_POINT('',(33.2719504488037,-161.887778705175,-0.00999999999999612));
#355=CARTESIAN_POINT('',(35.8385918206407,-171.199049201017,-0.00999999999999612));
#356=CARTESIAN_POINT('',(29.9803253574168,-178.254603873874,-0.00999999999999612));
#357=CARTESIAN_POINT('',(25.4737691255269,-186.687205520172,-0.00999999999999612));
#358=CARTESIAN_POINT('',(28.9610561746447,-203.576557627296,-0.00999999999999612));
#359=CARTESIAN_POINT('',(48.123587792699,-210.569059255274,-0.00999999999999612));
#360=CARTESIAN_POINT('',(64.640055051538,-207.443077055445,-0.00999999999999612));
#361=CARTESIAN_POINT('',(74.3525428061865,-199.315206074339,-0.00999999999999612));
#362=CARTESIAN_POINT('',(75.7823175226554,-188.025012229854,-0.00999999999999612));
#363=CARTESIAN_POINT('',(70.2823025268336,-180.424725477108,-0.00999999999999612));
#364=CARTESIAN_POINT('',(64.0173174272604,-173.04354513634,-0.00999999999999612));
#365=CARTESIAN_POINT('',(71.5185276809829,-158.021609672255,-0.00999999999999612));
#366=CARTESIAN_POINT('',(93.5727320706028,-159.248655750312,-0.00999999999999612));
#367=CARTESIAN_POINT('',(113.740225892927,-158.313305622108,-0.00999999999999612));
#368=CARTESIAN_POINT('',(131.949907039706,-158.592164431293,-0.00999999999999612));
#369=CARTESIAN_POINT('',(148.33531025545,-158.585790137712,-0.00999999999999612));
#370=CARTESIAN_POINT('',(161.926831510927,-159.545351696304,-0.00999999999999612));
#371=CARTESIAN_POINT('',(175.071227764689,-161.773214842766,-0.00999999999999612));
#372=CARTESIAN_POINT('',(191.617950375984,-167.262045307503,-0.00999999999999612));
#373=CARTESIAN_POINT('',(211.099842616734,-169.750201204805,-0.00999999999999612));
#374=CARTESIAN_POINT('',(231.162897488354,-172.887375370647,-0.00999999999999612));
#375=CARTESIAN_POINT('',(248.004345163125,-166.961938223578,-0.00999999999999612));
#376=CARTESIAN_POINT('',(246.8159561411,-153.026737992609,-0.00999999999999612));
#377=CARTESIAN_POINT('',(239.480844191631,-147.244126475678,-0.00999999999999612));
#378=CARTESIAN_POINT('',(236.934105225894,-136.316213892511,-0.00999999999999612));
#379=CARTESIAN_POINT('',(242.714843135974,-119.925321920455,-0.00999999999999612));
#380=CARTESIAN_POINT('',(261.920814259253,-116.243910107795,-0.00999999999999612));
#381=CARTESIAN_POINT('',(276.115384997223,-120.8163533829,-0.00999999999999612));
#382=CARTESIAN_POINT('',(283.920063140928,-128.519918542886,-0.00999999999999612));
#383=CARTESIAN_POINT('',(286.731045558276,-138.27620491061,-0.00999999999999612));
#384=CARTESIAN_POINT('',(285.530131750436,-148.336399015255,-0.00999999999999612));
#385=CARTESIAN_POINT('',(279.231187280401,-154.989394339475,-0.00999999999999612));
#386=CARTESIAN_POINT('',(277.47424541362,-164.19805137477,-0.00999999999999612));
#387=CARTESIAN_POINT('',(282.318065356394,-172.951788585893,-0.00999999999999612));
#388=CARTESIAN_POINT('',(296.661024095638,-174.046241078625,-0.00999999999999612));
#389=CARTESIAN_POINT('',(312.407790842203,-171.220247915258,-0.00999999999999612));
#390=CARTESIAN_POINT('',(331.258502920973,-165.499354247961,-0.00999999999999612));
#391=CARTESIAN_POINT('',(349.515462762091,-164.109048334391,-0.00999999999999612));
#392=CARTESIAN_POINT('',(369.065560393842,-162.668121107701,-0.00999999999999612));
#393=CARTESIAN_POINT('',(383.300131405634,-163.956688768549,-0.00999999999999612));
#394=CARTESIAN_POINT('',(393.167029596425,-163.158367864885,-0.00999999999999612));
#395=CARTESIAN_POINT('',(398.987630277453,-166.389896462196,-0.00999999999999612));
#396=CARTESIAN_POINT('',(404.84494808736,-173.902135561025,-0.00999999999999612));
#397=CARTESIAN_POINT('',(403.877710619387,-184.83720633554,-0.00999999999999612));
#398=CARTESIAN_POINT('',(397.972595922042,-188.779997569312,-0.00999999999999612));
#399=CARTESIAN_POINT('',(391.418741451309,-195.180814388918,-0.00999999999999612));
#400=CARTESIAN_POINT('',(389.486866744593,-207.78576343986,-0.00999999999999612));
#401=CARTESIAN_POINT('',(398.568510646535,-219.719050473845,-0.00999999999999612));
#402=CARTESIAN_POINT('',(413.367098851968,-224.627522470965,-0.00999999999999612));
#403=CARTESIAN_POINT('',(430.645527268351,-225.349016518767,-0.00999999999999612));
#404=CARTESIAN_POINT('',(445.119633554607,-217.990655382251,-0.00999999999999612));
#405=CARTESIAN_POINT('',(450.39877091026,-206.645471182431,-0.00999999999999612));
#406=CARTESIAN_POINT('',(448.623596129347,-196.883477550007,-0.00999999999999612));
#407=CARTESIAN_POINT('',(441.485570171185,-190.93342380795,-0.00999999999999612));
#408=CARTESIAN_POINT('',(437.838155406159,-181.169971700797,-0.00999999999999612));
#409=CARTESIAN_POINT('',(439.616707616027,-168.611761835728,-0.00999999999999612));
#410=CARTESIAN_POINT('',(452.865547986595,-163.032695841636,-0.00999999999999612));
#411=CARTESIAN_POINT('',(467.117395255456,-164.448128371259,-0.00999999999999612));
#412=CARTESIAN_POINT('',(487.604647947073,-165.665160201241,-0.00999999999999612));
#413=CARTESIAN_POINT('',(502.403051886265,-168.291679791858,-0.00999999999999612));
#414=CARTESIAN_POINT('',(512.,-168.072880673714,-0.00999999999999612));
#415=B_SPLINE_CURVE_WITH_KNOTS('',3,(#283,#284,#285,#286,#287,#288,#289,#290,#291,#292,#293,
#294,#295,#296,#297,#298,#299,#300,#301,#302,#303,#304,#305,#306,#307,#308,#309,#310,#311,#312,
#313,#314,#315,#316,#317,#318,#319,#320,#321,#322,#323,#324,#325,#326,#327,#328,#329,#330,#331,
#332,#333,#334,#335,#336,#337,#338,#339,#340,#341,#342,#343,#344,#345,#346,#347,#348,#349,#350,
#351,#352,#353,#354,#355,#356,#357,#358,#359,#360,#361,#362,#363,#364,#365,#366,#367,#368,#369,
#370,#371,#372,#373,#374,#375,#376,#377,#378,#379,#380,#381,#382,#383,#384,#385,#386,#387,#388,
#389,#390,#391,#392,#393,#394,#395,#396,#397,#398,#399,#400,#401,#402,#403,#404,#405,#406,#407,
#408,#409,#410,#411,#412,#413,#414),.UNSPECIFIED.,.F.,.F.,(4,1,1,1,1,1,1,1,1,1,1,1,1,1,1,1,1,1,
1,1,1,1,1,1,1,1,1,1,1,1,1,1,1,1,1,1,1,1,1,1,1,1,1,1,1,1,1,1,1,1,1,1,1,1,1,1,1,1,1,1,1,1,1,1,1,1,
1,1,1,1,1,1,1,1,1,1,1,1,1,1,1,1,1,1,1,1,1,1,1,1,1,1,1,1,1,1,1,1,1,1,1,1,1,1,1,1,1,1,1,1,1,1,1,1,
1,1,1,1,1,1,1,1,1,1,1,1,1,1,1,4),(0.,0.0165769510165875,0.0274671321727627,0.0371464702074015,
0.0400980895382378,0.0433463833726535,0.0497073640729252,0.0544453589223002,0.0588139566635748,
0.0681101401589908,0.0747959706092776,0.0809546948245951,0.0901532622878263,0.095867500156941,
0.102811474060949,0.111015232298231,0.116106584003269,0.121579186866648,0.125543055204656,
0.130677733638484,0.132270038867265,0.141466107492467,0.152619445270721,0.163261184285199,
0.17192085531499,0.184637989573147,0.201793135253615,0.207148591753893,0.211794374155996,
0.216266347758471,0.220719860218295,0.227137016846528,0.235715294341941,0.242716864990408,
0.253632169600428,0.260665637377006,0.267939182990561,0.274072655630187,0.278241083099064,
0.281904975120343,0.287053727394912,0.29279991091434,0.302640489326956,0.309919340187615,
0.319192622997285,0.328902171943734,0.341927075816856,0.349651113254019,0.359095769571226,
0.364234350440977,0.368518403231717,0.376844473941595,0.383449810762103,0.39383324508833,
0.403172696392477,0.412747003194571,0.419192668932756,0.426662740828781,0.433256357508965,
0.43915987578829,0.447945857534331,0.454784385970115,0.459263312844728,0.465316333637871,
0.467037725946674,0.476477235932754,0.496011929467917,0.506346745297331,0.520318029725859,
0.527127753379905,0.530814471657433,0.537296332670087,0.541421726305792,0.546659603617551,
0.554071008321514,0.569060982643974,0.576942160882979,0.583891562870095,0.590293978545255,
0.59495110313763,0.600623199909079,0.605913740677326,0.620422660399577,0.634553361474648,
0.643799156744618,0.652762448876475,0.66399167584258,0.668151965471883,0.676618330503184,
0.695209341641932,0.702656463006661,0.714264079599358,0.719592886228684,0.724033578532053,
0.730384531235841,0.738333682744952,0.752555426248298,0.759343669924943,0.764844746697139,
0.771407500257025,0.776939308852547,0.782103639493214,0.787257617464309,0.792861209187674,
0.797464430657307,0.811466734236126,0.822004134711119,0.832486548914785,0.844241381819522,
0.856894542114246,0.858607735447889,0.861373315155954,0.868279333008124,0.874872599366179,
0.877877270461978,0.880642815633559,0.89130639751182,0.896526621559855,0.906482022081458,
0.917930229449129,0.927070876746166,0.933622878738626,0.939051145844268,0.943432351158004,
0.949734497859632,0.957214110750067,0.963224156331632,0.97316531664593,0.98286869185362,1.),.UNSPECIFIED.);
#416=DIRECTION('',(0.,0.,1.));
#417=VECTOR('',#416,1.);
#418=SURFACE_OF_LINEAR_EXTRUSION('',#415,#417);
#419=CARTESIAN_POINT('',(-512.,-172.519287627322,20.));
#420=CARTESIAN_POINT('',(-502.879283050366,-170.962470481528,20.));
#421=CARTESIAN_POINT('',(-487.788222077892,-168.37828827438,20.));
#422=CARTESIAN_POINT('',(-467.037528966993,-166.739801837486,20.));
#423=CARTESIAN_POINT('',(-454.159365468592,-165.446436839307,20.));
#424=CARTESIAN_POINT('',(-444.971534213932,-166.107812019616,20.));
#425=CARTESIAN_POINT('',(-439.850321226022,-171.772015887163,20.));
#426=CARTESIAN_POINT('',(-440.374957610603,-181.037323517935,20.));
#427=CARTESIAN_POINT('',(-446.328241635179,-187.391856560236,20.));
#428=CARTESIAN_POINT('',(-453.905227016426,-194.752671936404,20.));
#429=CARTESIAN_POINT('',(-453.078389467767,-207.700641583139,20.));
#430=CARTESIAN_POINT('',(-447.147625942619,-218.930001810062,20.));
#431=CARTESIAN_POINT('',(-435.337181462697,-224.50074852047,20.));
#432=CARTESIAN_POINT('',(-423.146614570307,-223.01936726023,20.));
#433=CARTESIAN_POINT('',(-411.980938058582,-217.277205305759,20.));
#434=CARTESIAN_POINT('',(-406.065466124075,-206.648631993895,20.));
#435=CARTESIAN_POINT('',(-404.677696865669,-194.893000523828,20.));
#436=CARTESIAN_POINT('',(-408.988751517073,-185.080089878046,20.));
#437=CARTESIAN_POINT('',(-416.250714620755,-179.677092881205,20.));
#438=CARTESIAN_POINT('',(-414.534960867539,-170.559036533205,20.));
#439=CARTESIAN_POINT('',(-409.029101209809,-166.771377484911,20.));
#440=CARTESIAN_POINT('',(-399.765557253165,-166.088529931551,20.));
#441=CARTESIAN_POINT('',(-387.895154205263,-166.365956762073,20.));
#442=CARTESIAN_POINT('',(-370.467023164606,-166.815486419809,20.));
#443=CARTESIAN_POINT('',(-353.468929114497,-167.36046909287,20.));
#444=CARTESIAN_POINT('',(-335.945481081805,-171.004639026,20.));
#445=CARTESIAN_POINT('',(-314.642568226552,-174.308910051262,20.));
#446=CARTESIAN_POINT('',(-295.191530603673,-175.373190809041,20.));
#447=CARTESIAN_POINT('',(-279.655129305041,-174.532366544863,20.));
#448=CARTESIAN_POINT('',(-272.871357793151,-169.661223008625,20.));
#449=CARTESIAN_POINT('',(-269.507556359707,-161.549368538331,20.));
#450=CARTESIAN_POINT('',(-275.843021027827,-154.65628056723,20.));
#451=CARTESIAN_POINT('',(-280.95754914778,-144.902856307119,20.));
#452=CARTESIAN_POINT('',(-276.534312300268,-130.977346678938,20.));
#453=CARTESIAN_POINT('',(-261.937250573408,-125.579540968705,20.));
#454=CARTESIAN_POINT('',(-247.663642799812,-124.917748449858,20.));
#455=CARTESIAN_POINT('',(-234.462562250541,-132.547465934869,20.));
#456=CARTESIAN_POINT('',(-231.429981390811,-144.191054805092,20.));
#457=CARTESIAN_POINT('',(-232.066307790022,-154.613730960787,20.));
#458=CARTESIAN_POINT('',(-238.05545254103,-160.208195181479,20.));
#459=CARTESIAN_POINT('',(-239.725495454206,-167.504540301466,20.));
#460=CARTESIAN_POINT('',(-236.616853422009,-176.333406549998,20.));
#461=CARTESIAN_POINT('',(-223.934770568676,-178.282283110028,20.));
#462=CARTESIAN_POINT('',(-211.556635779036,-176.87255281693,20.));
#463=CARTESIAN_POINT('',(-197.283196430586,-172.884179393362,20.));
#464=CARTESIAN_POINT('',(-182.605892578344,-171.15728588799,20.));
#465=CARTESIAN_POINT('',(-164.840984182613,-173.659101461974,20.));
#466=CARTESIAN_POINT('',(-147.945056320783,-175.383809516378,20.));
#467=CARTESIAN_POINT('',(-131.023155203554,-175.064925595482,20.));
#468=CARTESIAN_POINT('',(-118.854077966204,-171.888086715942,20.));
#469=CARTESIAN_POINT('',(-110.251650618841,-164.015375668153,20.));
#470=CARTESIAN_POINT('',(-112.366058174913,-152.74022327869,20.));
#471=CARTESIAN_POINT('',(-124.029184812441,-149.21363367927,20.));
#472=CARTESIAN_POINT('',(-130.728576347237,-135.686086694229,20.));
#473=CARTESIAN_POINT('',(-127.173489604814,-119.738819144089,20.));
#474=CARTESIAN_POINT('',(-112.643680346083,-109.612236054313,20.));
#475=CARTESIAN_POINT('',(-97.8925044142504,-110.264465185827,20.));
#476=CARTESIAN_POINT('',(-85.3244606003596,-114.886626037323,20.));
#477=CARTESIAN_POINT('',(-77.7012738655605,-123.996273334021,20.));
#478=CARTESIAN_POINT('',(-75.1871896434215,-136.082021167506,20.));
#479=CARTESIAN_POINT('',(-83.4449300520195,-145.685757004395,20.));
#480=CARTESIAN_POINT('',(-93.6696383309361,-152.57821138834,20.));
#481=CARTESIAN_POINT('',(-93.6908124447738,-166.777041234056,20.));
#482=CARTESIAN_POINT('',(-84.1667136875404,-170.982620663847,20.));
#483=CARTESIAN_POINT('',(-77.6752461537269,-173.278649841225,20.));
#484=CARTESIAN_POINT('',(-68.1506335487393,-173.35598232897,20.));
#485=CARTESIAN_POINT('',(-50.9086392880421,-172.467654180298,20.));
#486=CARTESIAN_POINT('',(-29.3703336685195,-168.255680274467,20.));
#487=CARTESIAN_POINT('',(-5.85808978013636,-161.016855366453,20.));
#488=CARTESIAN_POINT('',(10.8279950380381,-157.928962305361,20.));
#489=CARTESIAN_POINT('',(25.2118575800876,-156.177147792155,20.));
#490=CARTESIAN_POINT('',(33.2719504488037,-161.887778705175,20.));
#491=CARTESIAN_POINT('',(35.8385918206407,-171.199049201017,20.));
#492=CARTESIAN_POINT('',(29.9803253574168,-178.254603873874,20.));
#493=CARTESIAN_POINT('',(25.4737691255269,-186.687205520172,20.));
#494=CARTESIAN_POINT('',(28.9610561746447,-203.576557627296,20.));
#495=CARTESIAN_POINT('',(48.123587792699,-210.569059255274,20.));
#496=CARTESIAN_POINT('',(64.640055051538,-207.443077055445,20.));
#497=CARTESIAN_POINT('',(74.3525428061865,-199.315206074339,20.));
#498=CARTESIAN_POINT('',(75.7823175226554,-188.025012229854,20.));
#499=CARTESIAN_POINT('',(70.2823025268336,-180.424725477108,20.));
#500=CARTESIAN_POINT('',(64.0173174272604,-173.04354513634,20.));
#501=CARTESIAN_POINT('',(71.5185276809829,-158.021609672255,20.));
#502=CARTESIAN_POINT('',(93.5727320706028,-159.248655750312,20.));
#503=CARTESIAN_POINT('',(113.740225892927,-158.313305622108,20.));
#504=CARTESIAN_POINT('',(131.949907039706,-158.592164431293,20.));
#505=CARTESIAN_POINT('',(148.33531025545,-158.585790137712,20.));
#506=CARTESIAN_POINT('',(161.926831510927,-159.545351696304,20.));
#507=CARTESIAN_POINT('',(175.071227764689,-161.773214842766,20.));
#508=CARTESIAN_POINT('',(191.617950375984,-167.262045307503,20.));
#509=CARTESIAN_POINT('',(211.099842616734,-169.750201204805,20.));
#510=CARTESIAN_POINT('',(231.162897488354,-172.887375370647,20.));
#511=CARTESIAN_POINT('',(248.004345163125,-166.961938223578,20.));
#512=CARTESIAN_POINT('',(246.8159561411,-153.026737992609,20.));
#513=CARTESIAN_POINT('',(239.480844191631,-147.244126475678,20.));
#514=CARTESIAN_POINT('',(236.934105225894,-136.316213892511,20.));
#515=CARTESIAN_POINT('',(242.714843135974,-119.925321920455,20.));
#516=CARTESIAN_POINT('',(261.920814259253,-116.243910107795,20.));
#517=CARTESIAN_POINT('',(276.115384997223,-120.8163533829,20.));
#518=CARTESIAN_POINT('',(283.920063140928,-128.519918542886,20.));
#519=CARTESIAN_POINT('',(286.731045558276,-138.27620491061,20.));
#520=CARTESIAN_POINT('',(285.530131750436,-148.336399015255,20.));
#521=CARTESIAN_POINT('',(279.231187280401,-154.989394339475,20.));
#522=CARTESIAN_POINT('',(277.47424541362,-164.19805137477,20.));
#523=CARTESIAN_POINT('',(282.318065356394,-172.951788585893,20.));
#524=CARTESIAN_POINT('',(296.661024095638,-174.046241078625,20.));
#525=CARTESIAN_POINT('',(312.407790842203,-171.220247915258,20.));
#526=CARTESIAN_POINT('',(331.258502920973,-165.499354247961,20.));
#527=CARTESIAN_POINT('',(349.515462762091,-164.109048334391,20.));
#528=CARTESIAN_POINT('',(369.065560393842,-162.668121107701,20.));
#529=CARTESIAN_POINT('',(383.300131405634,-163.956688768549,20.));
#530=CARTESIAN_POINT('',(393.167029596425,-163.158367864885,20.));
#531=CARTESIAN_POINT('',(398.987630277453,-166.389896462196,20.));
#532=CARTESIAN_POINT('',(404.84494808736,-173.902135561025,20.));
#533=CARTESIAN_POINT('',(403.877710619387,-184.83720633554,20.));
#534=CARTESIAN_POINT('',(397.972595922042,-188.779997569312,20.));
#535=CARTESIAN_POINT('',(391.418741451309,-195.180814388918,20.));
#536=CARTESIAN_POINT('',(389.486866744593,-207.78576343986,20.));
#537=CARTESIAN_POINT('',(398.568510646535,-219.719050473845,20.));
#538=CARTESIAN_POINT('',(413.367098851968,-224.627522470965,20.));
#539=CARTESIAN_POINT('',(430.645527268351,-225.349016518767,20.));
#540=CARTESIAN_POINT('',(445.119633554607,-217.990655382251,20.));
#541=CARTESIAN_POINT('',(450.39877091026,-206.645471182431,20.));
#542=CARTESIAN_POINT('',(448.623596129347,-196.883477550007,20.));
#543=CARTESIAN_POINT('',(441.485570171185,-190.93342380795,20.));
#544=CARTESIAN_POINT('',(437.838155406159,-181.169971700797,20.));
#545=CARTESIAN_POINT('',(439.616707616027,-168.611761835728,20.));
#546=CARTESIAN_POINT('',(452.865547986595,-163.032695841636,20.));
#547=CARTESIAN_POINT('',(467.117395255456,-164.448128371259,20.));
#548=CARTESIAN_POINT('',(487.604647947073,-165.665160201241,20.));
#549=CARTESIAN_POINT('',(502.403051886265,-168.291679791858,20.));
#550=CARTESIAN_POINT('',(512.,-168.072880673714,20.));
#551=B_SPLINE_CURVE_WITH_KNOTS('',3,(#419,#420,#421,#422,#423,#424,#425,#426,#427,#428,#429,
#430,#431,#432,#433,#434,#435,#436,#437,#438,#439,#440,#441,#442,#443,#444,#445,#446,#447,#448,
#449,#450,#451,#452,#453,#454,#455,#456,#457,#458,#459,#460,#461,#462,#463,#464,#465,#466,#467,
#468,#469,#470,#471,#472,#473,#474,#475,#476,#477,#478,#479,#480,#481,#482,#483,#484,#485,#486,
#487,#488,#489,#490,#491,#492,#493,#494,#495,#496,#497,#498,#499,#500,#501,#502,#503,#504,#505,
#506,#507,#508,#509,#510,#511,#512,#513,#514,#515,#516,#517,#518,#519,#520,#521,#522,#523,#524,
#525,#526,#527,#528,#529,#530,#531,#532,#533,#534,#535,#536,#537,#538,#539,#540,#541,#542,#543,
#544,#545,#546,#547,#548,#549,#550),.UNSPECIFIED.,.F.,.F.,(4,1,1,1,1,1,1,1,1,1,1,1,1,1,1,1,1,1,
1,1,1,1,1,1,1,1,1,1,1,1,1,1,1,1,1,1,1,1,1,1,1,1,1,1,1,1,1,1,1,1,1,1,1,1,1,1,1,1,1,1,1,1,1,1,1,1,
1,1,1,1,1,1,1,1,1,1,1,1,1,1,1,1,1,1,1,1,1,1,1,1,1,1,1,1,1,1,1,1,1,1,1,1,1,1,1,1,1,1,1,1,1,1,1,1,
1,1,1,1,1,1,1,1,1,1,1,1,1,1,1,4),(0.,0.0165769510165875,0.0274671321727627,0.0371464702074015,
0.0400980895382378,0.0433463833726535,0.0497073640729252,0.0544453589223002,0.0588139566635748,
0.0681101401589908,0.0747959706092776,0.0809546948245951,0.0901532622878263,0.095867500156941,
0.102811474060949,0.111015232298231,0.116106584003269,0.121579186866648,0.125543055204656,
0.130677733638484,0.132270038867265,0.141466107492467,0.152619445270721,0.163261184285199,
0.17192085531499,0.184637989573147,0.201793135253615,0.207148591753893,0.211794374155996,
0.216266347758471,0.220719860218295,0.227137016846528,0.235715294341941,0.242716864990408,
0.253632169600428,0.260665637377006,0.267939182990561,0.274072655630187,0.278241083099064,
0.281904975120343,0.287053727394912,0.29279991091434,0.302640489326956,0.309919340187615,
0.319192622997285,0.328902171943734,0.341927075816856,0.349651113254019,0.359095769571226,
0.364234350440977,0.368518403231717,0.376844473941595,0.383449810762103,0.39383324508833,
0.403172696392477,0.412747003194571,0.419192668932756,0.426662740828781,0.433256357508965,
0.43915987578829,0.447945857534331,0.454784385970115,0.459263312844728,0.465316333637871,
0.467037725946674,0.476477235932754,0.496011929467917,0.506346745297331,0.520318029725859,
0.527127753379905,0.530814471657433,0.537296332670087,0.541421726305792,0.546659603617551,
0.554071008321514,0.569060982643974,0.576942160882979,0.583891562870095,0.590293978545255,
0.59495110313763,0.600623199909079,0.605913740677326,0.620422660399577,0.634553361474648,
0.643799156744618,0.652762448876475,0.66399167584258,0.668151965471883,0.676618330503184,
0.695209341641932,0.702656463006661,0.714264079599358,0.719592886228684,0.724033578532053,
0.730384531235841,0.738333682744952,0.752555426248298,0.759343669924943,0.764844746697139,
0.771407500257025,0.776939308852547,0.782103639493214,0.787257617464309,0.792861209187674,
0.797464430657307,0.811466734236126,0.822004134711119,0.832486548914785,0.844241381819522,
0.856894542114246,0.858607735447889,0.861373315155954,0.868279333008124,0.874872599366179,
0.877877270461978,0.880642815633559,0.89130639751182,0.896526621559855,0.906482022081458,
0.917930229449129,0.927070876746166,0.933622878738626,0.939051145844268,0.943432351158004,
0.949734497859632,0.957214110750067,0.963224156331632,0.97316531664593,0.98286869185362,1.),.UNSPECIFIED.);
#552=CARTESIAN_POINT('',(-512.,-172.519287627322,20.));
#553=VERTEX_POINT('',#552);
#554=EDGE_CURVE('E11',#553,#179,#551,.T.);
#555=ORIENTED_EDGE('',*,*,#554,.T.);
#556=ORIENTED_EDGE('',*,*,#278,.T.);
#557=CARTESIAN_POINT('',(-512.,-172.519287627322,0.));
#558=CARTESIAN_POINT('',(-502.879283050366,-170.962470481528,0.));
#559=CARTESIAN_POINT('',(-487.788222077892,-168.37828827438,0.));
#560=CARTESIAN_POINT('',(-467.037528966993,-166.739801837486,0.));
#561=CARTESIAN_POINT('',(-454.159365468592,-165.446436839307,0.));
#562=CARTESIAN_POINT('',(-444.971534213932,-166.107812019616,0.));
#563=CARTESIAN_POINT('',(-439.850321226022,-171.772015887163,0.));
#564=CARTESIAN_POINT('',(-440.374957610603,-181.037323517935,0.));
#565=CARTESIAN_POINT('',(-446.328241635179,-187.391856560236,0.));
#566=CARTESIAN_POINT('',(-453.905227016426,-194.752671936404,0.));
#567=CARTESIAN_POINT('',(-453.078389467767,-207.700641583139,0.));
#568=CARTESIAN_POINT('',(-447.147625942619,-218.930001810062,0.));
#569=CARTESIAN_POINT('',(-435.337181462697,-224.50074852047,0.));
#570=CARTESIAN_POINT('',(-423.146614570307,-223.01936726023,0.));
#571=CARTESIAN_POINT('',(-411.980938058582,-217.277205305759,0.));
#572=CARTESIAN_POINT('',(-406.065466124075,-206.648631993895,0.));
#573=CARTESIAN_POINT('',(-404.677696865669,-194.893000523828,0.));
#574=CARTESIAN_POINT('',(-408.988751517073,-185.080089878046,0.));
#575=CARTESIAN_POINT('',(-416.250714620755,-179.677092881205,0.));
#576=CARTESIAN_POINT('',(-414.534960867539,-170.559036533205,0.));
#577=CARTESIAN_POINT('',(-409.029101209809,-166.771377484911,0.));
#578=CARTESIAN_POINT('',(-399.765557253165,-166.088529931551,0.));
#579=CARTESIAN_POINT('',(-387.895154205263,-166.365956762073,0.));
#580=CARTESIAN_POINT('',(-370.467023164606,-166.815486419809,0.));
#581=CARTESIAN_POINT('',(-353.468929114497,-167.36046909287,0.));
#582=CARTESIAN_POINT('',(-335.945481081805,-171.004639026,0.));
#583=CARTESIAN_POINT('',(-314.642568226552,-174.308910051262,0.));
#584=CARTESIAN_POINT('',(-295.191530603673,-175.373190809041,0.));
#585=CARTESIAN_POINT('',(-279.655129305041,-174.532366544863,0.));
#586=CARTESIAN_POINT('',(-272.871357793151,-169.661223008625,0.));
#587=CARTESIAN_POINT('',(-269.507556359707,-161.549368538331,0.));
#588=CARTESIAN_POINT('',(-275.843021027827,-154.65628056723,0.));
#589=CARTESIAN_POINT('',(-280.95754914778,-144.902856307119,0.));
#590=CARTESIAN_POINT('',(-276.534312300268,-130.977346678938,0.));
#591=CARTESIAN_POINT('',(-261.937250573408,-125.579540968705,0.));
#592=CARTESIAN_POINT('',(-247.663642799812,-124.917748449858,0.));
#593=CARTESIAN_POINT('',(-234.462562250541,-132.547465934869,0.));
#594=CARTESIAN_POINT('',(-231.429981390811,-144.191054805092,0.));
#595=CARTESIAN_POINT('',(-232.066307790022,-154.613730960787,0.));
#596=CARTESIAN_POINT('',(-238.05545254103,-160.208195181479,0.));
#597=CARTESIAN_POINT('',(-239.725495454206,-167.504540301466,0.));
#598=CARTESIAN_POINT('',(-236.616853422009,-176.333406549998,0.));
#599=CARTESIAN_POINT('',(-223.934770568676,-178.282283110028,0.));
#600=CARTESIAN_POINT('',(-211.556635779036,-176.87255281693,0.));
#601=CARTESIAN_POINT('',(-197.283196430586,-172.884179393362,0.));
#602=CARTESIAN_POINT('',(-182.605892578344,-171.15728588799,0.));
#603=CARTESIAN_POINT('',(-164.840984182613,-173.659101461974,0.));
#604=CARTESIAN_POINT('',(-147.945056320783,-175.383809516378,0.));
#605=CARTESIAN_POINT('',(-131.023155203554,-175.064925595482,0.));
#606=CARTESIAN_POINT('',(-118.854077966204,-171.888086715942,0.));
#607=CARTESIAN_POINT('',(-110.251650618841,-164.015375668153,0.));
#608=CARTESIAN_POINT('',(-112.366058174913,-152.74022327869,0.));
#609=CARTESIAN_POINT('',(-124.029184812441,-149.21363367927,0.));
#610=CARTESIAN_POINT('',(-130.728576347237,-135.686086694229,0.));
#611=CARTESIAN_POINT('',(-127.173489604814,-119.738819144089,0.));
#612=CARTESIAN_POINT('',(-112.643680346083,-109.612236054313,0.));
#613=CARTESIAN_POINT('',(-97.8925044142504,-110.264465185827,0.));
#614=CARTESIAN_POINT('',(-85.3244606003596,-114.886626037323,0.));
#615=CARTESIAN_POINT('',(-77.7012738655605,-123.996273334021,0.));
#616=CARTESIAN_POINT('',(-75.1871896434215,-136.082021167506,0.));
#617=CARTESIAN_POINT('',(-83.4449300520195,-145.685757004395,0.));
#618=CARTESIAN_POINT('',(-93.6696383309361,-152.57821138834,0.));
#619=CARTESIAN_POINT('',(-93.6908124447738,-166.777041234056,0.));
#620=CARTESIAN_POINT('',(-84.1667136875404,-170.982620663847,0.));
#621=CARTESIAN_POINT('',(-77.6752461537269,-173.278649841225,0.));
#622=CARTESIAN_POINT('',(-68.1506335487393,-173.35598232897,0.));
#623=CARTESIAN_POINT('',(-50.9086392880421,-172.467654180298,0.));
#624=CARTESIAN_POINT('',(-29.3703336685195,-168.255680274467,0.));
#625=CARTESIAN_POINT('',(-5.85808978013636,-161.016855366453,0.));
#626=CARTESIAN_POINT('',(10.8279950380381,-157.928962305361,0.));
#627=CARTESIAN_POINT('',(25.2118575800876,-156.177147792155,0.));
#628=CARTESIAN_POINT('',(33.2719504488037,-161.887778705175,0.));
#629=CARTESIAN_POINT('',(35.8385918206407,-171.199049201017,0.));
#630=CARTESIAN_POINT('',(29.9803253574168,-178.254603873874,0.));
#631=CARTESIAN_POINT('',(25.4737691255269,-186.687205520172,0.));
#632=CARTESIAN_POINT('',(28.9610561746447,-203.576557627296,0.));
#633=CARTESIAN_POINT('',(48.123587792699,-210.569059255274,0.));
#634=CARTESIAN_POINT('',(64.640055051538,-207.443077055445,0.));
#635=CARTESIAN_POINT('',(74.3525428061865,-199.315206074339,0.));
#636=CARTESIAN_POINT('',(75.7823175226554,-188.025012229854,0.));
#637=CARTESIAN_POINT('',(70.2823025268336,-180.424725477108,0.));
#638=CARTESIAN_POINT('',(64.0173174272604,-173.04354513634,0.));
#639=CARTESIAN_POINT('',(71.5185276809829,-158.021609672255,0.));
#640=CARTESIAN_POINT('',(93.5727320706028,-159.248655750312,0.));
#641=CARTESIAN_POINT('',(113.740225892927,-158.313305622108,0.));
#642=CARTESIAN_POINT('',(131.949907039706,-158.592164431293,0.));
#643=CARTESIAN_POINT('',(148.33531025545,-158.585790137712,0.));
#644=CARTESIAN_POINT('',(161.926831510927,-159.545351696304,0.));
#645=CARTESIAN_POINT('',(175.071227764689,-161.773214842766,0.));
#646=CARTESIAN_POINT('',(191.617950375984,-167.262045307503,0.));
#647=CARTESIAN_POINT('',(211.099842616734,-169.750201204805,0.));
#648=CARTESIAN_POINT('',(231.162897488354,-172.887375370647,0.));
#649=CARTESIAN_POINT('',(248.004345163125,-166.961938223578,0.));
#650=CARTESIAN_POINT('',(246.8159561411,-153.026737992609,0.));
#651=CARTESIAN_POINT('',(239.480844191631,-147.244126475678,0.));
#652=CARTESIAN_POINT('',(236.934105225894,-136.316213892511,0.));
#653=CARTESIAN_POINT('',(242.714843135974,-119.925321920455,0.));
#654=CARTESIAN_POINT('',(261.920814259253,-116.243910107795,0.));
#655=CARTESIAN_POINT('',(276.115384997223,-120.8163533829,0.));
#656=CARTESIAN_POINT('',(283.920063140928,-128.519918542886,0.));
#657=CARTESIAN_POINT('',(286.731045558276,-138.27620491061,0.));
#658=CARTESIAN_POINT('',(285.530131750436,-148.336399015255,0.));
#659=CARTESIAN_POINT('',(279.231187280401,-154.989394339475,0.));
#660=CARTESIAN_POINT('',(277.47424541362,-164.19805137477,0.));
#661=CARTESIAN_POINT('',(282.318065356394,-172.951788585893,0.));
#662=CARTESIAN_POINT('',(296.661024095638,-174.046241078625,0.));
#663=CARTESIAN_POINT('',(312.407790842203,-171.220247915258,0.));
#664=CARTESIAN_POINT('',(331.258502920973,-165.499354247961,0.));
#665=CARTESIAN_POINT('',(349.515462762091,-164.109048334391,0.));
#666=CARTESIAN_POINT('',(369.065560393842,-162.668121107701,0.));
#667=CARTESIAN_POINT('',(383.300131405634,-163.956688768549,0.));
#668=CARTESIAN_POINT('',(393.167029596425,-163.158367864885,0.));
#669=CARTESIAN_POINT('',(398.987630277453,-166.389896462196,0.));
#670=CARTESIAN_POINT('',(404.84494808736,-173.902135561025,0.));
#671=CARTESIAN_POINT('',(403.877710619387,-184.83720633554,0.));
#672=CARTESIAN_POINT('',(397.972595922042,-188.779997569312,0.));
#673=CARTESIAN_POINT('',(391.418741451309,-195.180814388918,0.));
#674=CARTESIAN_POINT('',(389.486866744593,-207.78576343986,0.));
#675=CARTESIAN_POINT('',(398.568510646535,-219.719050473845,0.));
#676=CARTESIAN_POINT('',(413.367098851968,-224.627522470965,0.));
#677=CARTESIAN_POINT('',(430.645527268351,-225.349016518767,0.));
#678=CARTESIAN_POINT('',(445.119633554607,-217.990655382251,0.));
#679=CARTESIAN_POINT('',(450.39877091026,-206.645471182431,0.));
#680=CARTESIAN_POINT('',(448.623596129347,-196.883477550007,0.));
#681=CARTESIAN_POINT('',(441.485570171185,-190.93342380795,0.));
#682=CARTESIAN_POINT('',(437.838155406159,-181.169971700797,0.));
#683=CARTESIAN_POINT('',(439.616707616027,-168.611761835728,0.));
#684=CARTESIAN_POINT('',(452.865547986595,-163.032695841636,0.));
#685=CARTESIAN_POINT('',(467.117395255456,-164.448128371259,0.));
#686=CARTESIAN_POINT('',(487.604647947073,-165.665160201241,0.));
#687=CARTESIAN_POINT('',(502.403051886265,-168.291679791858,0.));
#688=CARTESIAN_POINT('',(512.,-168.072880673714,0.));
#689=B_SPLINE_CURVE_WITH_KNOTS('',3,(#557,#558,#559,#560,#561,#562,#563,#564,#565,#566,#567,
#568,#569,#570,#571,#572,#573,#574,#575,#576,#577,#578,#579,#580,#581,#582,#583,#584,#585,#586,
#587,#588,#589,#590,#591,#592,#593,#594,#595,#596,#597,#598,#599,#600,#601,#602,#603,#604,#605,
#606,#607,#608,#609,#610,#611,#612,#613,#614,#615,#616,#617,#618,#619,#620,#621,#622,#623,#624,
#625,#626,#627,#628,#629,#630,#631,#632,#633,#634,#635,#636,#637,#638,#639,#640,#641,#642,#643,
#644,#645,#646,#647,#648,#649,#650,#651,#652,#653,#654,#655,#656,#657,#658,#659,#660,#661,#662,
#663,#664,#665,#666,#667,#668,#669,#670,#671,#672,#673,#674,#675,#676,#677,#678,#679,#680,#681,
#682,#683,#684,#685,#686,#687,#688),.UNSPECIFIED.,.F.,.F.,(4,1,1,1,1,1,1,1,1,1,1,1,1,1,1,1,1,1,
1,1,1,1,1,1,1,1,1,1,1,1,1,1,1,1,1,1,1,1,1,1,1,1,1,1,1,1,1,1,1,1,1,1,1,1,1,1,1,1,1,1,1,1,1,1,1,1,
1,1,1,1,1,1,1,1,1,1,1,1,1,1,1,1,1,1,1,1,1,1,1,1,1,1,1,1,1,1,1,1,1,1,1,1,1,1,1,1,1,1,1,1,1,1,1,1,
1,1,1,1,1,1,1,1,1,1,1,1,1,1,1,4),(0.,0.0165769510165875,0.0274671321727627,0.0371464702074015,
0.0400980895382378,0.0433463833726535,0.0497073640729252,0.0544453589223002,0.0588139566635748,
0.0681101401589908,0.0747959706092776,0.0809546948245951,0.0901532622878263,0.095867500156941,
0.102811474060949,0.111015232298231,0.116106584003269,0.121579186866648,0.125543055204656,
0.130677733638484,0.132270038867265,0.141466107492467,0.152619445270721,0.163261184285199,
0.17192085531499,0.184637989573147,0.201793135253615,0.207148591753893,0.211794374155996,
0.216266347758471,0.220719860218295,0.227137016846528,0.235715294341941,0.242716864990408,
0.253632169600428,0.260665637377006,0.267939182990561,0.274072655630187,0.278241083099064,
0.281904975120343,0.287053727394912,0.29279991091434,0.302640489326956,0.309919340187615,
0.319192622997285,0.328902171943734,0.341927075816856,0.349651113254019,0.359095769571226,
0.364234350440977,0.368518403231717,0.376844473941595,0.383449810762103,0.39383324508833,
0.403172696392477,0.412747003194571,0.419192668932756,0.426662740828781,0.433256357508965,
0.43915987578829,0.447945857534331,0.454784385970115,0.459263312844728,0.465316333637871,
0.467037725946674,0.476477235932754,0.496011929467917,0.506346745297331,0.520318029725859,
0.527127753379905,0.530814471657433,0.537296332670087,0.541421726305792,0.546659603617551,
0.554071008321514,0.569060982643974,0.576942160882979,0.583891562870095,0.590293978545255,
0.59495110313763,0.600623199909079,0.605913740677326,0.620422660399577,0.634553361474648,
0.643799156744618,0.652762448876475,0.66399167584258,0.668151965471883,0.676618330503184,
0.695209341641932,0.702656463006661,0.714264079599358,0.719592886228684,0.724033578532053,
0.730384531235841,0.738333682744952,0.752555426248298,0.759343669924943,0.764844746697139,
0.771407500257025,0.776939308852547,0.782103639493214,0.787257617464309,0.792861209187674,
0.797464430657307,0.811466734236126,0.822004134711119,0.832486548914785,0.844241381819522,
0.856894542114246,0.858607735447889,0.861373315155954,0.868279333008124,0.874872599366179,
0.877877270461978,0.880642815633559,0.89130639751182,0.896526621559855,0.906482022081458,
0.917930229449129,0.927070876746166,0.933622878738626,0.939051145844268,0.943432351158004,
0.949734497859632,0.957214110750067,0.963224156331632,0.97316531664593,0.98286869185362,1.),.UNSPECIFIED.);
#690=CARTESIAN_POINT('',(-512.,-172.519287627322,0.));
#691=VERTEX_POINT('',#690);
#692=EDGE_CURVE('E58',#691,#271,#689,.T.);
#693=ORIENTED_EDGE('',*,*,#692,.F.);
#694=DIRECTION('',(0.,0.,1.));
#695=VECTOR('',#694,1.);
#696=CARTESIAN_POINT('',(-512.,-172.519287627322,-0.00999999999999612));
#697=LINE('',#696,#695);
#698=EDGE_CURVE('E45',#553,#691,#697,.F.);
#699=ORIENTED_EDGE('',*,*,#698,.F.);
#700=EDGE_LOOP('',(#555,#556,#693,#699));
#701=FACE_BOUND('',#700,.T.);
#702=ADVANCED_FACE('F88',(#701),#418,.F.);
#703=CARTESIAN_POINT('',(-512.,-356.,20.));
#704=DIRECTION('',(1.,0.,0.));
#705=DIRECTION('',(0.,0.,-1.));
#706=AXIS2_PLACEMENT_3D('',#703,#704,#705);
#707=PLANE('',#706);
#708=DIRECTION('',(0.,-1.,0.));
#709=VECTOR('',#708,1.);
#710=CARTESIAN_POINT('',(-512.,-356.,20.));
#711=LINE('',#710,#709);
#712=CARTESIAN_POINT('',(-512.,-356.,20.));
#713=VERTEX_POINT('',#712);
#714=EDGE_CURVE('E94',#553,#713,#711,.T.);
#715=ORIENTED_EDGE('',*,*,#714,.F.);
#716=ORIENTED_EDGE('',*,*,#698,.T.);
#717=DIRECTION('',(0.,-1.,0.));
#718=VECTOR('',#717,1.);
#719=CARTESIAN_POINT('',(-512.,-356.,0.));
#720=LINE('',#719,#718);
#721=CARTESIAN_POINT('',(-512.,-356.,0.));
#722=VERTEX_POINT('',#721);
#723=EDGE_CURVE('E102',#691,#722,#720,.T.);
#724=ORIENTED_EDGE('',*,*,#723,.T.);
#725=DIRECTION('',(0.,0.,-1.));
#726=VECTOR('',#725,1.);
#727=CARTESIAN_POINT('',(-512.,-356.,20.));
#728=LINE('',#727,#726);
#729=EDGE_CURVE('E97',#713,#722,#728,.T.);
#730=ORIENTED_EDGE('',*,*,#729,.F.);
#731=EDGE_LOOP('',(#715,#716,#724,#730));
#732=FACE_BOUND('',#731,.T.);
#733=ADVANCED_FACE('F95',(#732),#707,.F.);
#734=CARTESIAN_POINT('',(512.,-356.,20.));
#735=DIRECTION('',(0.,1.,0.));
#736=DIRECTION('',(-1.,0.,0.));
#737=AXIS2_PLACEMENT_3D('',#734,#735,#736);
#738=PLANE('',#737);
#739=DIRECTION('',(1.,0.,0.));
#740=VECTOR('',#739,1.);
#741=CARTESIAN_POINT('',(512.,-356.,0.));
#742=LINE('',#741,#740);
#743=EDGE_CURVE('E98',#722,#189,#742,.T.);
#744=ORIENTED_EDGE('',*,*,#743,.T.);
#745=ORIENTED_EDGE('',*,*,#190,.T.);
#746=DIRECTION('',(1.,0.,0.));
#747=VECTOR('',#746,1.);
#748=CARTESIAN_POINT('',(512.,-356.,20.));
#749=LINE('',#748,#747);
#750=EDGE_CURVE('E86',#713,#181,#749,.T.);
#751=ORIENTED_EDGE('',*,*,#750,.F.);
#752=ORIENTED_EDGE('',*,*,#729,.T.);
#753=EDGE_LOOP('',(#744,#745,#751,#752));
#754=FACE_BOUND('',#753,.T.);
#755=ADVANCED_FACE('F139',(#754),#738,.F.);
#756=CARTESIAN_POINT('',(0.,0.,20.));
#757=DIRECTION('',(0.,0.,1.));
#758=DIRECTION('',(1.,0.,0.));
#759=AXIS2_PLACEMENT_3D('',#756,#757,#758);
#760=PLANE('',#759);
#761=ORIENTED_EDGE('',*,*,#182,.F.);
#762=ORIENTED_EDGE('',*,*,#554,.F.);
#763=ORIENTED_EDGE('',*,*,#714,.T.);
#764=ORIENTED_EDGE('',*,*,#750,.T.);
#765=EDGE_LOOP('',(#761,#762,#763,#764));
#766=FACE_BOUND('',#765,.T.);
#767=ADVANCED_FACE('F36',(#766),#760,.T.);
#768=CARTESIAN_POINT('',(0.,0.,0.));
#769=DIRECTION('',(0.,0.,1.));
#770=DIRECTION('',(1.,0.,0.));
#771=AXIS2_PLACEMENT_3D('',#768,#769,#770);
#772=PLANE('',#771);
#773=ORIENTED_EDGE('',*,*,#692,.T.);
#774=ORIENTED_EDGE('',*,*,#272,.T.);
#775=ORIENTED_EDGE('',*,*,#743,.F.);
#776=ORIENTED_EDGE('',*,*,#723,.F.);
#777=EDGE_LOOP('',(#773,#774,#775,#776));
#778=FACE_BOUND('',#777,.T.);
#779=ADVANCED_FACE('F144',(#778),#772,.F.);
#780=CLOSED_SHELL('',(#282,#702,#733,#755,#767,#779));
#781=MANIFOLD_SOLID_BREP('B2',#780);
#782=ADVANCED_BREP_SHAPE_REPRESENTATION('',(#18,#781),#14);
#783=SHAPE_DEFINITION_REPRESENTATION(#9,#782);
ENDSEC;
END-ISO-10303-21;
